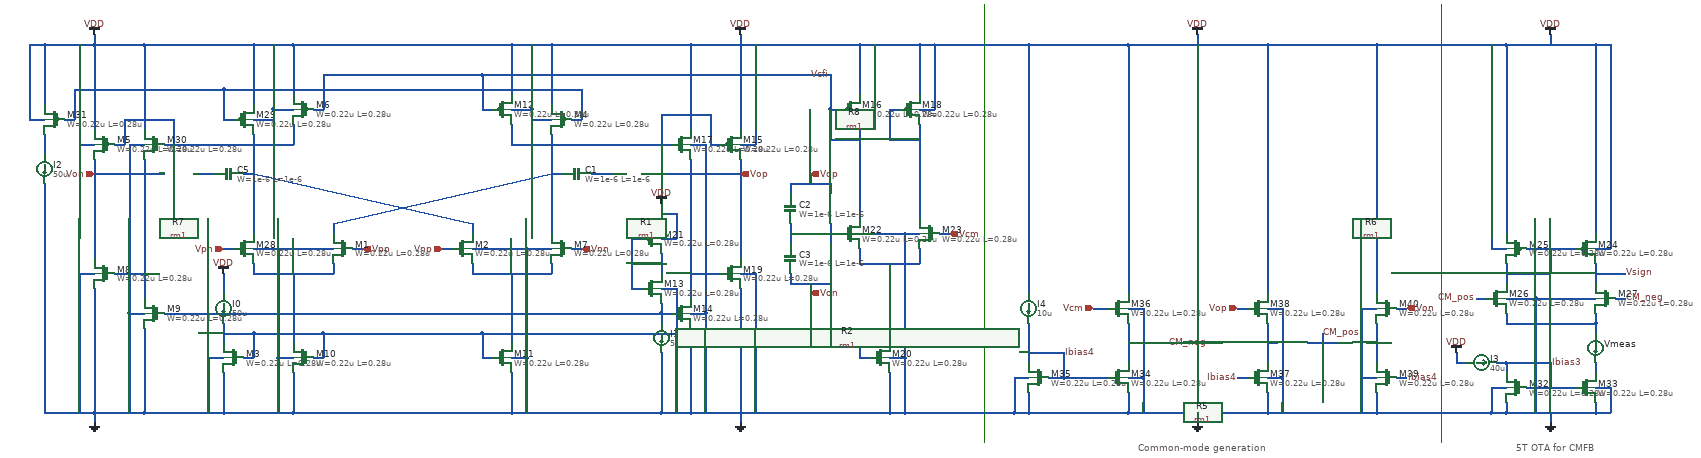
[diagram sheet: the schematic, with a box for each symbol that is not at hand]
v {xschem version=3.4.8RC file_version=1.3}
G {}
K {}
V {}
S {}
F {}
E {}
L 4 2030 -1660 2030 -780 {}
L 4 2950 -1660 2950 -780 {}
T {5T OTA for CMFB} 3100 -780 0 0 0.4 0.4 {}
T {Common-mode generation} 2340 -780 0 0 0.4 0.4 {}
N 560 -1400 560 -1200 {lab=#net1}
N 720 -1140 720 -1120 {lab=#net2}
N 560 -1120 720 -1120 {lab=#net2}
N 560 -1140 560 -1120 {lab=#net2}
N 1160 -1400 1160 -1200 {lab=#net3}
N 1000 -1140 1000 -1120 {lab=#net4}
N 1000 -1120 1160 -1120 {lab=#net4}
N 1160 -1140 1160 -1120 {lab=#net4}
N 140 -1400 140 -1360 {lab=#net5}
N 140 -1580 140 -1460 {lab=VDD}
N 140 -1580 240 -1580 {lab=VDD}
N 240 -1580 340 -1580 {lab=VDD}
N 140 -1300 140 -840 {lab=GND}
N 240 -1090 240 -840 {lab=GND}
N 140 -840 240 -840 {lab=GND}
N 340 -1010 340 -840 {lab=GND}
N 240 -840 340 -840 {lab=GND}
N 500 -1430 520 -1430 {lab=#net6}
N 280 -1120 340 -1120 {lab=#net7}
N 340 -840 500 -840 {lab=GND}
N 500 -840 640 -840 {lab=GND}
N 640 -840 1080 -840 {lab=GND}
N 560 -1580 560 -1460 {lab=VDD}
N 340 -1580 560 -1580 {lab=VDD}
N 720 -1220 720 -1200 {lab=#net3}
N 1000 -1220 1000 -1200 {lab=#net1}
N 240 -1350 240 -1150 {lab=Von}
N 340 -1350 340 -1070 {lab=#net7}
N 240 -1580 240 -1410 {lab=VDD}
N 340 -1580 340 -1410 {lab=VDD}
N 380 -1380 560 -1380 {lab=#net1}
N 400 -1430 400 -1380 {lab=#net1}
N 300 -1430 400 -1430 {lab=#net1}
N 300 -1430 300 -1380 {lab=#net1}
N 280 -1380 300 -1380 {lab=#net1}
N 560 -1380 640 -1380 {lab=#net1}
N 640 -1420 640 -1380 {lab=#net1}
N 640 -1580 640 -1480 {lab=VDD}
N 560 -1580 640 -1580 {lab=VDD}
N 680 -1450 700 -1450 {lab=Vcfi}
N 1020 -1450 1040 -1450 {lab=Vcfi}
N 1080 -1420 1080 -1380 {lab=#net3}
N 1080 -1380 1160 -1380 {lab=#net3}
N 640 -1580 1080 -1580 {lab=VDD}
N 1080 -1580 1080 -1480 {lab=VDD}
N 1080 -1580 1160 -1580 {lab=VDD}
N 1160 -1580 1160 -1460 {lab=VDD}
N 1480 -1380 1500 -1380 {lab=#net3}
N 1480 -1440 1480 -1380 {lab=#net3}
N 1380 -1440 1480 -1440 {lab=#net3}
N 1380 -1440 1380 -1380 {lab=#net3}
N 1440 -1580 1440 -1410 {lab=VDD}
N 1540 -1580 1540 -1410 {lab=VDD}
N 1440 -1580 1540 -1580 {lab=VDD}
N 1440 -1350 1440 -1070 {lab=#net8}
N 1440 -1010 1440 -840 {lab=GND}
N 1440 -1120 1500 -1120 {lab=#net8}
N 1540 -1350 1540 -1150 {lab=Vop}
N 1540 -1090 1540 -840 {lab=GND}
N 1440 -840 1540 -840 {lab=GND}
N 1320 -1090 1340 -1090 {lab=#net9}
N 1320 -1190 1320 -1090 {lab=#net9}
N 1320 -1190 1340 -1190 {lab=#net9}
N 1380 -1160 1380 -1120 {lab=#net9}
N 1320 -1140 1380 -1140 {lab=#net9}
N 1380 -1040 1380 -1020 {lab=#net10}
N 1380 -1060 1380 -1040 {lab=#net10}
N 1380 -960 1380 -840 {lab=GND}
N 1080 -840 1380 -840 {lab=GND}
N 1380 -840 1440 -840 {lab=GND}
N 380 -1040 1380 -1040 {lab=#net10}
N 1380 -1040 1400 -1040 {lab=#net10}
N 1160 -1380 1400 -1380 {lab=#net3}
N 1160 -1580 1440 -1580 {lab=VDD}
N 1200 -1170 1220 -1170 {lab=Vnn}
N 940 -1170 960 -1170 {lab=Vnp}
N 760 -1170 780 -1170 {lab=Vpp}
N 500 -1170 520 -1170 {lab=Vpn}
N 1720 -1450 1740 -1450 {lab=Vcfi}
N 1720 -1450 1720 -1390 {lab=Vcfi}
N 1720 -1390 1780 -1390 {lab=Vcfi}
N 1840 -1450 1860 -1450 {lab=#net11}
N 1840 -1450 1840 -1390 {lab=#net11}
N 1840 -1390 1900 -1390 {lab=#net11}
N 720 -1220 1160 -1320 {lab=#net3}
N 560 -1320 1000 -1220 {lab=#net1}
N 1780 -1420 1780 -1230 {lab=Vcfi}
N 1900 -1420 1900 -1230 {lab=#net11}
N 1720 -1220 1720 -1180 {lab=#net12}
N 1640 -1220 1640 -1180 {lab=#net12}
N 1640 -1300 1640 -1280 {lab=Vop}
N 1640 -1300 1720 -1300 {lab=Vop}
N 1720 -1300 1720 -1280 {lab=Vop}
N 1720 -1120 1720 -1100 {lab=Von}
N 1640 -1100 1720 -1100 {lab=Von}
N 1640 -1120 1640 -1100 {lab=Von}
N 1720 -1200 1740 -1200 {lab=#net12}
N 1640 -1200 1720 -1200 {lab=#net12}
N 1540 -1580 1780 -1580 {lab=VDD}
N 1780 -1580 1780 -1480 {lab=VDD}
N 1780 -1580 1900 -1580 {lab=VDD}
N 1900 -1580 1900 -1480 {lab=VDD}
N 1900 -1170 1900 -1140 {lab=#net13}
N 1780 -1140 1900 -1140 {lab=#net13}
N 1780 -1170 1780 -1140 {lab=#net13}
N 1540 -840 1840 -840 {lab=GND}
N 1940 -1200 1960 -1200 {lab=Vcm}
N 1680 -1320 1680 -1300 {lab=Vop}
N 1680 -1100 1680 -1080 {lab=Von}
N 500 -920 500 -840 {lab=GND}
N 1080 -920 1080 -840 {lab=GND}
N 1840 -920 1840 -840 {lab=GND}
N 1840 -1140 1840 -980 {lab=#net13}
N 640 -1120 640 -980 {lab=#net2}
N 1080 -1120 1080 -980 {lab=#net4}
N 500 -1000 560 -1000 {lab=#net14}
N 560 -1000 560 -950 {lab=#net14}
N 540 -950 560 -950 {lab=#net14}
N 680 -950 700 -950 {lab=#net14}
N 700 -1000 700 -950 {lab=#net14}
N 560 -1000 700 -1000 {lab=#net14}
N 700 -1000 1020 -1000 {lab=#net14}
N 1020 -1000 1020 -950 {lab=#net14}
N 1020 -950 1040 -950 {lab=#net14}
N 1020 -1000 1780 -1000 {lab=#net14}
N 1780 -1000 1780 -950 {lab=#net14}
N 1780 -950 1800 -950 {lab=#net14}
N 180 -1430 200 -1430 {lab=#net6}
N 640 -920 640 -840 {lab=GND}
N 1200 -1430 1220 -1430 {lab=#net6}
N 600 -1450 640 -1450 {lab=VDD}
N 600 -1450 600 -1430 {lab=VDD}
N 560 -1430 600 -1430 {lab=VDD}
N 1080 -1450 1120 -1450 {lab=VDD}
N 1120 -1450 1120 -1430 {lab=VDD}
N 1120 -1430 1160 -1430 {lab=VDD}
N 1900 -1450 1930 -1450 {lab=VDD}
N 1780 -1450 1810 -1450 {lab=VDD}
N 1540 -1380 1570 -1380 {lab=VDD}
N 1840 -950 1870 -950 {lab=GND}
N 1440 -1040 1470 -1040 {lab=GND}
N 1380 -1090 1410 -1090 {lab=GND}
N 1540 -1120 1570 -1120 {lab=GND}
N 1440 -1380 1470 -1380 {lab=GND}
N 470 -950 500 -950 {lab=GND}
N 610 -950 640 -950 {lab=GND}
N 310 -1040 340 -1040 {lab=GND}
N 210 -1120 240 -1120 {lab=GND}
N 310 -1380 340 -1380 {lab=GND}
N 3120 -1170 3220 -1170 {lab=#net15}
N 3300 -1070 3320 -1070 {lab=CM_neg}
N 3020 -1070 3040 -1070 {lab=CM_pos}
N 3170 -1170 3170 -1120 {lab=#net15}
N 3080 -1120 3170 -1120 {lab=#net15}
N 3080 -1040 3080 -1020 {lab=#net16}
N 3080 -1020 3260 -1020 {lab=#net16}
N 3260 -1040 3260 -1020 {lab=#net16}
N 3120 -890 3220 -890 {lab=Ibias3}
N 3170 -940 3170 -890 {lab=Ibias3}
N 3080 -940 3170 -940 {lab=Ibias3}
N 3260 -860 3260 -840 {lab=GND}
N 3080 -840 3260 -840 {lab=GND}
N 3080 -860 3080 -840 {lab=GND}
N 2860 -1050 2880 -1050 {lab=Von}
N 2540 -1050 2560 -1050 {lab=Vop}
N 3260 -1120 3320 -1120 {lab=Vsign}
N 2820 -1020 2820 -940 {lab=#net17}
N 2600 -1020 2600 -940 {lab=#net18}
N 2600 -880 2600 -840 {lab=GND}
N 2600 -840 2820 -840 {lab=GND}
N 2820 -880 2820 -840 {lab=GND}
N 2790 -910 2820 -910 {lab=GND}
N 2790 -910 2790 -840 {lab=GND}
N 2630 -910 2630 -840 {lab=GND}
N 2600 -910 2630 -910 {lab=GND}
N 2160 -910 2190 -910 {lab=Ibias4}
N 2190 -960 2190 -910 {lab=Ibias4}
N 2120 -960 2190 -960 {lab=Ibias4}
N 2190 -910 2280 -910 {lab=Ibias4}
N 2320 -1020 2320 -940 {lab=CM_neg}
N 2320 -840 2600 -840 {lab=GND}
N 2320 -880 2320 -840 {lab=GND}
N 2120 -840 2320 -840 {lab=GND}
N 2120 -880 2120 -840 {lab=GND}
N 2090 -910 2120 -910 {lab=GND}
N 2090 -910 2090 -840 {lab=GND}
N 2090 -840 2120 -840 {lab=GND}
N 2320 -910 2350 -910 {lab=GND}
N 2350 -910 2350 -840 {lab=GND}
N 2320 -1050 2350 -1050 {lab=GND}
N 2350 -1050 2350 -910 {lab=GND}
N 2600 -1050 2630 -1050 {lab=GND}
N 2630 -1050 2630 -910 {lab=GND}
N 2790 -1050 2820 -1050 {lab=GND}
N 2790 -1050 2790 -910 {lab=GND}
N 2250 -1050 2280 -1050 {lab=Vcm}
N 2320 -980 2400 -980 {lab=CM_neg}
N 2680 -980 2740 -980 {lab=CM_pos}
N 2600 -980 2620 -980 {lab=#net18}
N 2800 -980 2820 -980 {lab=#net17}
N 2710 -1000 2710 -980 {lab=CM_pos}
N 2540 -910 2560 -910 {lab=Ibias4}
N 2860 -910 2880 -910 {lab=Ibias4}
N 1720 -1520 1720 -1450 {lab=Vcfi}
N 1020 -1520 1720 -1520 {lab=Vcfi}
N 1020 -1520 1020 -1450 {lab=Vcfi}
N 700 -1520 1020 -1520 {lab=Vcfi}
N 700 -1520 700 -1450 {lab=Vcfi}
N 1220 -1490 1220 -1430 {lab=#net6}
N 500 -1490 1220 -1490 {lab=#net6}
N 500 -1490 500 -1430 {lab=#net6}
N 200 -1490 500 -1490 {lab=#net6}
N 200 -1490 200 -1430 {lab=#net6}
N 600 -1580 600 -1450 {lab=VDD}
N 1120 -1580 1120 -1450 {lab=VDD}
N 3080 -1140 3080 -1100 {lab=#net15}
N 3260 -1140 3260 -1100 {lab=Vsign}
N 3060 -940 3080 -940 {lab=Ibias3}
N 2980 -940 3000 -940 {lab=VDD}
N 2980 -960 2980 -940 {lab=VDD}
N 3080 -940 3080 -920 {lab=Ibias3}
N 3260 -940 3260 -920 {lab=#net19}
N 3260 -1020 3260 -1000 {lab=#net16}
N 3050 -1170 3080 -1170 {lab=VDD}
N 3260 -1170 3290 -1170 {lab=VDD}
N 3260 -890 3290 -890 {lab=GND}
N 3290 -890 3290 -840 {lab=GND}
N 3260 -840 3290 -840 {lab=GND}
N 3050 -840 3080 -840 {lab=GND}
N 3050 -890 3050 -840 {lab=GND}
N 3050 -890 3080 -890 {lab=GND}
N 1870 -950 1870 -840 {lab=GND}
N 1840 -840 1870 -840 {lab=GND}
N 1470 -1040 1470 -840 {lab=GND}
N 1080 -950 1110 -950 {lab=GND}
N 1110 -950 1110 -840 {lab=GND}
N 610 -950 610 -840 {lab=GND}
N 470 -950 470 -840 {lab=GND}
N 310 -1040 310 -840 {lab=GND}
N 210 -1120 210 -840 {lab=GND}
N 540 -1320 560 -1320 {lab=#net1}
N 440 -1320 480 -1320 {lab=#net20}
N 240 -1320 380 -1320 {lab=Von}
N 1160 -1320 1180 -1320 {lab=#net3}
N 1240 -1320 1280 -1320 {lab=#net21}
N 1340 -1320 1540 -1320 {lab=Vop}
N 1930 -1580 1930 -1450 {lab=VDD}
N 1900 -1580 1930 -1580 {lab=VDD}
N 1810 -1580 1810 -1450 {lab=VDD}
N 1570 -1580 1570 -1380 {lab=VDD}
N 210 -1380 240 -1380 {lab=VDD}
N 210 -1580 210 -1380 {lab=VDD}
N 110 -1430 140 -1430 {lab=VDD}
N 110 -1580 110 -1430 {lab=VDD}
N 110 -1580 140 -1580 {lab=VDD}
N 1870 -1200 1870 -950 {lab=GND}
N 1870 -1200 1900 -1200 {lab=GND}
N 1780 -1200 1870 -1200 {lab=GND}
N 1470 -1380 1470 -1040 {lab=GND}
N 1570 -1120 1570 -840 {lab=GND}
N 1110 -1170 1110 -950 {lab=GND}
N 1110 -1170 1160 -1170 {lab=GND}
N 1000 -1170 1110 -1170 {lab=GND}
N 610 -1170 610 -950 {lab=GND}
N 560 -1170 610 -1170 {lab=GND}
N 610 -1170 720 -1170 {lab=GND}
N 3140 -1070 3140 -840 {lab=GND}
N 3080 -1070 3140 -1070 {lab=GND}
N 3140 -1070 3260 -1070 {lab=GND}
N 500 -1120 500 -1080 {lab=VDD}
N 500 -1020 500 -980 {lab=#net14}
N 1380 -1260 1380 -1220 {lab=VDD}
N 1380 -1190 1410 -1190 {lab=VDD}
N 1410 -1240 1410 -1190 {lab=VDD}
N 1380 -1240 1410 -1240 {lab=VDD}
N 1410 -1090 1410 -840 {lab=GND}
N 2120 -1020 2120 -940 {lab=Ibias4}
N 240 -840 240 -820 {lab=GND}
N 1540 -840 1540 -820 {lab=GND}
N 2460 -840 2460 -820 {lab=GND}
N 3170 -840 3170 -820 {lab=GND}
N 240 -1600 240 -1580 {lab=VDD}
N 1540 -1600 1540 -1580 {lab=VDD}
N 2820 -840 3050 -840 {lab=GND}
N 2120 -1580 2120 -1080 {lab=VDD}
N 2320 -1580 2320 -1080 {lab=VDD}
N 2120 -1580 2320 -1580 {lab=VDD}
N 2600 -1580 2600 -1080 {lab=VDD}
N 2320 -1580 2600 -1580 {lab=VDD}
N 2820 -1580 2820 -1080 {lab=VDD}
N 2600 -1580 2820 -1580 {lab=VDD}
N 3080 -1580 3080 -1200 {lab=VDD}
N 2820 -1580 3080 -1580 {lab=VDD}
N 3260 -1580 3260 -1200 {lab=VDD}
N 3080 -1580 3260 -1580 {lab=VDD}
N 3050 -1580 3050 -1170 {lab=VDD}
N 3290 -1580 3290 -1170 {lab=VDD}
N 3260 -1580 3290 -1580 {lab=VDD}
N 2460 -1600 2460 -1580 {lab=VDD}
N 3170 -1600 3170 -1580 {lab=VDD}
N 1930 -1580 2120 -1580 {lab=VDD}
N 1870 -840 2090 -840 {lab=GND}
N 310 -1380 310 -1040 {lab=GND}
C {ipin.sym} 500 -1170 0 0 {name=p1 lab=Vpn}
C {ipin.sym} 780 -1170 0 1 {name=p2 lab=Vpp}
C {ipin.sym} 940 -1170 0 0 {name=p3 lab=Vnp}
C {ipin.sym} 1220 -1170 0 1 {name=p4 lab=Vnn}
C {isource.sym} 500 -1050 0 0 {name=I0 value=50u}
C {isource.sym} 1380 -990 0 0 {name=I1 value=50u}
C {isource.sym} 140 -1330 0 0 {name=I2 value=50u}
C {opin.sym} 1680 -1080 0 0 {name=p12 lab=Von}
C {opin.sym} 1680 -1320 0 0 {name=p10 lab=Vop}
C {opin.sym} 1540 -1320 0 0 {name=p11 lab=Vop}
C {opin.sym} 240 -1320 0 1 {name=p13 lab=Von}
C {lab_wire.sym} 1720 -1520 0 0 {name=p14 sig_type=std_logic lab=Vcfi}
C {symbols/nfet_03v3.sym} 540 -1170 0 0 {name=M28
L=0.28u
W=0.22u
nf=1
m=1
ad="'int((nf+1)/2) * W/nf * 0.18u'"
pd="'2*int((nf+1)/2) * (W/nf + 0.18u)'"
as="'int((nf+2)/2) * W/nf * 0.18u'"
ps="'2*int((nf+2)/2) * (W/nf + 0.18u)'"
nrd="'0.18u / W'" nrs="'0.18u / W'"
sa=0 sb=0 sd=0
model=nfet_03v3
spiceprefix=X
}
C {symbols/pfet_03v3.sym} 540 -1430 0 0 {name=M29
L=0.28u
W=0.22u
nf=1
m=1
ad="'int((nf+1)/2) * W/nf * 0.18u'"
pd="'2*int((nf+1)/2) * (W/nf + 0.18u)'"
as="'int((nf+2)/2) * W/nf * 0.18u'"
ps="'2*int((nf+2)/2) * (W/nf + 0.18u)'"
nrd="'0.18u / W'" nrs="'0.18u / W'"
sa=0 sb=0 sd=0
model=pfet_03v3
spiceprefix=X
}
C {gnd.sym} 240 -820 0 0 {name=l1 lab=GND}
C {vdd.sym} 240 -1600 0 0 {name=l2 lab=VDD}
C {symbols/nfet_03v3.sym} 360 -1380 0 1 {name=M30
L=0.28u
W=0.22u
nf=1
m=1
ad="'int((nf+1)/2) * W/nf * 0.18u'"
pd="'2*int((nf+1)/2) * (W/nf + 0.18u)'"
as="'int((nf+2)/2) * W/nf * 0.18u'"
ps="'2*int((nf+2)/2) * (W/nf + 0.18u)'"
nrd="'0.18u / W'" nrs="'0.18u / W'"
sa=0 sb=0 sd=0
model=nfet_03v3
spiceprefix=X
}
C {symbols/pfet_03v3.sym} 160 -1430 0 1 {name=M31
L=0.28u
W=0.22u
nf=1
m=1
ad="'int((nf+1)/2) * W/nf * 0.18u'"
pd="'2*int((nf+1)/2) * (W/nf + 0.18u)'"
as="'int((nf+2)/2) * W/nf * 0.18u'"
ps="'2*int((nf+2)/2) * (W/nf + 0.18u)'"
nrd="'0.18u / W'" nrs="'0.18u / W'"
sa=0 sb=0 sd=0
model=pfet_03v3
spiceprefix=X
}
C {symbols/pfet_03v3.sym} 260 -1380 0 1 {name=M5
L=0.28u
W=0.22u
nf=1
m=1
ad="'int((nf+1)/2) * W/nf * 0.18u'"
pd="'2*int((nf+1)/2) * (W/nf + 0.18u)'"
as="'int((nf+2)/2) * W/nf * 0.18u'"
ps="'2*int((nf+2)/2) * (W/nf + 0.18u)'"
nrd="'0.18u / W'" nrs="'0.18u / W'"
sa=0 sb=0 sd=0
model=pfet_03v3
spiceprefix=X
}
C {symbols/pfet_03v3.sym} 660 -1450 0 1 {name=M6
L=0.28u
W=0.22u
nf=1
m=1
ad="'int((nf+1)/2) * W/nf * 0.18u'"
pd="'2*int((nf+1)/2) * (W/nf + 0.18u)'"
as="'int((nf+2)/2) * W/nf * 0.18u'"
ps="'2*int((nf+2)/2) * (W/nf + 0.18u)'"
nrd="'0.18u / W'" nrs="'0.18u / W'"
sa=0 sb=0 sd=0
model=pfet_03v3
spiceprefix=X
}
C {symbols/pfet_03v3.sym} 1180 -1430 0 1 {name=M4
L=0.28u
W=0.22u
nf=1
m=1
ad="'int((nf+1)/2) * W/nf * 0.18u'"
pd="'2*int((nf+1)/2) * (W/nf + 0.18u)'"
as="'int((nf+2)/2) * W/nf * 0.18u'"
ps="'2*int((nf+2)/2) * (W/nf + 0.18u)'"
nrd="'0.18u / W'" nrs="'0.18u / W'"
sa=0 sb=0 sd=0
model=pfet_03v3
spiceprefix=X
}
C {symbols/pfet_03v3.sym} 1060 -1450 0 0 {name=M12
L=0.28u
W=0.22u
nf=1
m=1
ad="'int((nf+1)/2) * W/nf * 0.18u'"
pd="'2*int((nf+1)/2) * (W/nf + 0.18u)'"
as="'int((nf+2)/2) * W/nf * 0.18u'"
ps="'2*int((nf+2)/2) * (W/nf + 0.18u)'"
nrd="'0.18u / W'" nrs="'0.18u / W'"
sa=0 sb=0 sd=0
model=pfet_03v3
spiceprefix=X
}
C {symbols/pfet_03v3.sym} 1520 -1380 0 0 {name=M15
L=0.28u
W=0.22u
nf=1
m=1
ad="'int((nf+1)/2) * W/nf * 0.18u'"
pd="'2*int((nf+1)/2) * (W/nf + 0.18u)'"
as="'int((nf+2)/2) * W/nf * 0.18u'"
ps="'2*int((nf+2)/2) * (W/nf + 0.18u)'"
nrd="'0.18u / W'" nrs="'0.18u / W'"
sa=0 sb=0 sd=0
model=pfet_03v3
spiceprefix=X
}
C {symbols/pfet_03v3.sym} 1760 -1450 0 0 {name=M16
L=0.28u
W=0.22u
nf=1
m=1
ad="'int((nf+1)/2) * W/nf * 0.18u'"
pd="'2*int((nf+1)/2) * (W/nf + 0.18u)'"
as="'int((nf+2)/2) * W/nf * 0.18u'"
ps="'2*int((nf+2)/2) * (W/nf + 0.18u)'"
nrd="'0.18u / W'" nrs="'0.18u / W'"
sa=0 sb=0 sd=0
model=pfet_03v3
spiceprefix=X
}
C {symbols/pfet_03v3.sym} 1880 -1450 0 0 {name=M18
L=0.28u
W=0.22u
nf=1
m=1
ad="'int((nf+1)/2) * W/nf * 0.18u'"
pd="'2*int((nf+1)/2) * (W/nf + 0.18u)'"
as="'int((nf+2)/2) * W/nf * 0.18u'"
ps="'2*int((nf+2)/2) * (W/nf + 0.18u)'"
nrd="'0.18u / W'" nrs="'0.18u / W'"
sa=0 sb=0 sd=0
model=pfet_03v3
spiceprefix=X
}
C {symbols/pfet_03v3.sym} 1360 -1190 0 0 {name=M21
L=0.28u
W=0.22u
nf=1
m=1
ad="'int((nf+1)/2) * W/nf * 0.18u'"
pd="'2*int((nf+1)/2) * (W/nf + 0.18u)'"
as="'int((nf+2)/2) * W/nf * 0.18u'"
ps="'2*int((nf+2)/2) * (W/nf + 0.18u)'"
nrd="'0.18u / W'" nrs="'0.18u / W'"
sa=0 sb=0 sd=0
model=pfet_03v3
spiceprefix=X
}
C {symbols/nfet_03v3.sym} 740 -1170 0 1 {name=M1
L=0.28u
W=0.22u
nf=1
m=1
ad="'int((nf+1)/2) * W/nf * 0.18u'"
pd="'2*int((nf+1)/2) * (W/nf + 0.18u)'"
as="'int((nf+2)/2) * W/nf * 0.18u'"
ps="'2*int((nf+2)/2) * (W/nf + 0.18u)'"
nrd="'0.18u / W'" nrs="'0.18u / W'"
sa=0 sb=0 sd=0
model=nfet_03v3
spiceprefix=X
}
C {symbols/nfet_03v3.sym} 980 -1170 0 0 {name=M2
L=0.28u
W=0.22u
nf=1
m=1
ad="'int((nf+1)/2) * W/nf * 0.18u'"
pd="'2*int((nf+1)/2) * (W/nf + 0.18u)'"
as="'int((nf+2)/2) * W/nf * 0.18u'"
ps="'2*int((nf+2)/2) * (W/nf + 0.18u)'"
nrd="'0.18u / W'" nrs="'0.18u / W'"
sa=0 sb=0 sd=0
model=nfet_03v3
spiceprefix=X
}
C {symbols/nfet_03v3.sym} 1180 -1170 0 1 {name=M7
L=0.28u
W=0.22u
nf=1
m=1
ad="'int((nf+1)/2) * W/nf * 0.18u'"
pd="'2*int((nf+1)/2) * (W/nf + 0.18u)'"
as="'int((nf+2)/2) * W/nf * 0.18u'"
ps="'2*int((nf+2)/2) * (W/nf + 0.18u)'"
nrd="'0.18u / W'" nrs="'0.18u / W'"
sa=0 sb=0 sd=0
model=nfet_03v3
spiceprefix=X
}
C {symbols/nfet_03v3.sym} 520 -950 0 1 {name=M3
L=0.28u
W=0.22u
nf=1
m=1
ad="'int((nf+1)/2) * W/nf * 0.18u'"
pd="'2*int((nf+1)/2) * (W/nf + 0.18u)'"
as="'int((nf+2)/2) * W/nf * 0.18u'"
ps="'2*int((nf+2)/2) * (W/nf + 0.18u)'"
nrd="'0.18u / W'" nrs="'0.18u / W'"
sa=0 sb=0 sd=0
model=nfet_03v3
spiceprefix=X
}
C {symbols/nfet_03v3.sym} 660 -950 0 1 {name=M10
L=0.28u
W=0.22u
nf=1
m=1
ad="'int((nf+1)/2) * W/nf * 0.18u'"
pd="'2*int((nf+1)/2) * (W/nf + 0.18u)'"
as="'int((nf+2)/2) * W/nf * 0.18u'"
ps="'2*int((nf+2)/2) * (W/nf + 0.18u)'"
nrd="'0.18u / W'" nrs="'0.18u / W'"
sa=0 sb=0 sd=0
model=nfet_03v3
spiceprefix=X
}
C {symbols/nfet_03v3.sym} 1060 -950 0 0 {name=M11
L=0.28u
W=0.22u
nf=1
m=1
ad="'int((nf+1)/2) * W/nf * 0.18u'"
pd="'2*int((nf+1)/2) * (W/nf + 0.18u)'"
as="'int((nf+2)/2) * W/nf * 0.18u'"
ps="'2*int((nf+2)/2) * (W/nf + 0.18u)'"
nrd="'0.18u / W'" nrs="'0.18u / W'"
sa=0 sb=0 sd=0
model=nfet_03v3
spiceprefix=X
}
C {symbols/nfet_03v3.sym} 1360 -1090 0 0 {name=M13
L=0.28u
W=0.22u
nf=1
m=1
ad="'int((nf+1)/2) * W/nf * 0.18u'"
pd="'2*int((nf+1)/2) * (W/nf + 0.18u)'"
as="'int((nf+2)/2) * W/nf * 0.18u'"
ps="'2*int((nf+2)/2) * (W/nf + 0.18u)'"
nrd="'0.18u / W'" nrs="'0.18u / W'"
sa=0 sb=0 sd=0
model=nfet_03v3
spiceprefix=X
}
C {symbols/nfet_03v3.sym} 1420 -1040 0 0 {name=M14
L=0.28u
W=0.22u
nf=1
m=1
ad="'int((nf+1)/2) * W/nf * 0.18u'"
pd="'2*int((nf+1)/2) * (W/nf + 0.18u)'"
as="'int((nf+2)/2) * W/nf * 0.18u'"
ps="'2*int((nf+2)/2) * (W/nf + 0.18u)'"
nrd="'0.18u / W'" nrs="'0.18u / W'"
sa=0 sb=0 sd=0
model=nfet_03v3
spiceprefix=X
}
C {symbols/nfet_03v3.sym} 1520 -1120 0 0 {name=M19
L=0.28u
W=0.22u
nf=1
m=1
ad="'int((nf+1)/2) * W/nf * 0.18u'"
pd="'2*int((nf+1)/2) * (W/nf + 0.18u)'"
as="'int((nf+2)/2) * W/nf * 0.18u'"
ps="'2*int((nf+2)/2) * (W/nf + 0.18u)'"
nrd="'0.18u / W'" nrs="'0.18u / W'"
sa=0 sb=0 sd=0
model=nfet_03v3
spiceprefix=X
}
C {symbols/nfet_03v3.sym} 1820 -950 0 0 {name=M20
L=0.28u
W=0.22u
nf=1
m=1
ad="'int((nf+1)/2) * W/nf * 0.18u'"
pd="'2*int((nf+1)/2) * (W/nf + 0.18u)'"
as="'int((nf+2)/2) * W/nf * 0.18u'"
ps="'2*int((nf+2)/2) * (W/nf + 0.18u)'"
nrd="'0.18u / W'" nrs="'0.18u / W'"
sa=0 sb=0 sd=0
model=nfet_03v3
spiceprefix=X
}
C {symbols/nfet_03v3.sym} 1760 -1200 0 0 {name=M22
L=0.28u
W=0.22u
nf=1
m=1
ad="'int((nf+1)/2) * W/nf * 0.18u'"
pd="'2*int((nf+1)/2) * (W/nf + 0.18u)'"
as="'int((nf+2)/2) * W/nf * 0.18u'"
ps="'2*int((nf+2)/2) * (W/nf + 0.18u)'"
nrd="'0.18u / W'" nrs="'0.18u / W'"
sa=0 sb=0 sd=0
model=nfet_03v3
spiceprefix=X
}
C {symbols/nfet_03v3.sym} 1420 -1380 0 0 {name=M17
L=0.28u
W=0.22u
nf=1
m=1
ad="'int((nf+1)/2) * W/nf * 0.18u'"
pd="'2*int((nf+1)/2) * (W/nf + 0.18u)'"
as="'int((nf+2)/2) * W/nf * 0.18u'"
ps="'2*int((nf+2)/2) * (W/nf + 0.18u)'"
nrd="'0.18u / W'" nrs="'0.18u / W'"
sa=0 sb=0 sd=0
model=nfet_03v3
spiceprefix=X
}
C {symbols/nfet_03v3.sym} 260 -1120 0 1 {name=M8
L=0.28u
W=0.22u
nf=1
m=1
ad="'int((nf+1)/2) * W/nf * 0.18u'"
pd="'2*int((nf+1)/2) * (W/nf + 0.18u)'"
as="'int((nf+2)/2) * W/nf * 0.18u'"
ps="'2*int((nf+2)/2) * (W/nf + 0.18u)'"
nrd="'0.18u / W'" nrs="'0.18u / W'"
sa=0 sb=0 sd=0
model=nfet_03v3
spiceprefix=X
}
C {symbols/nfet_03v3.sym} 360 -1040 0 1 {name=M9
L=0.28u
W=0.22u
nf=1
m=1
ad="'int((nf+1)/2) * W/nf * 0.18u'"
pd="'2*int((nf+1)/2) * (W/nf + 0.18u)'"
as="'int((nf+2)/2) * W/nf * 0.18u'"
ps="'2*int((nf+2)/2) * (W/nf + 0.18u)'"
nrd="'0.18u / W'" nrs="'0.18u / W'"
sa=0 sb=0 sd=0
model=nfet_03v3
spiceprefix=X
}
C {symbols/nfet_03v3.sym} 1920 -1200 0 1 {name=M23
L=0.28u
W=0.22u
nf=1
m=1
ad="'int((nf+1)/2) * W/nf * 0.18u'"
pd="'2*int((nf+1)/2) * (W/nf + 0.18u)'"
as="'int((nf+2)/2) * W/nf * 0.18u'"
ps="'2*int((nf+2)/2) * (W/nf + 0.18u)'"
nrd="'0.18u / W'" nrs="'0.18u / W'"
sa=0 sb=0 sd=0
model=nfet_03v3
spiceprefix=X
}
C {gnd.sym} 1540 -820 0 0 {name=l11 lab=GND}
C {vdd.sym} 1540 -1600 0 0 {name=l12 lab=VDD}
C {symbols/pfet_03v3.sym} 3240 -1170 0 0 {name=M24
L=0.28u
W=0.22u
nf=1
m=1
ad="'int((nf+1)/2) * W/nf * 0.18u'"
pd="'2*int((nf+1)/2) * (W/nf + 0.18u)'"
as="'int((nf+2)/2) * W/nf * 0.18u'"
ps="'2*int((nf+2)/2) * (W/nf + 0.18u)'"
nrd="'0.18u / W'" nrs="'0.18u / W'"
sa=0 sb=0 sd=0
model=pfet_03v3
spiceprefix=X
}
C {symbols/pfet_03v3.sym} 3100 -1170 0 1 {name=M25
L=0.28u
W=0.22u
nf=1
m=1
ad="'int((nf+1)/2) * W/nf * 0.18u'"
pd="'2*int((nf+1)/2) * (W/nf + 0.18u)'"
as="'int((nf+2)/2) * W/nf * 0.18u'"
ps="'2*int((nf+2)/2) * (W/nf + 0.18u)'"
nrd="'0.18u / W'" nrs="'0.18u / W'"
sa=0 sb=0 sd=0
model=pfet_03v3
spiceprefix=X
}
C {symbols/nfet_03v3.sym} 3060 -1070 0 0 {name=M26
L=0.28u
W=0.22u
nf=1
m=1
ad="'int((nf+1)/2) * W/nf * 0.18u'"
pd="'2*int((nf+1)/2) * (W/nf + 0.18u)'"
as="'int((nf+2)/2) * W/nf * 0.18u'"
ps="'2*int((nf+2)/2) * (W/nf + 0.18u)'"
nrd="'0.18u / W'" nrs="'0.18u / W'"
sa=0 sb=0 sd=0
model=nfet_03v3
spiceprefix=X
}
C {symbols/nfet_03v3.sym} 3280 -1070 0 1 {name=M27
L=0.28u
W=0.22u
nf=1
m=1
ad="'int((nf+1)/2) * W/nf * 0.18u'"
pd="'2*int((nf+1)/2) * (W/nf + 0.18u)'"
as="'int((nf+2)/2) * W/nf * 0.18u'"
ps="'2*int((nf+2)/2) * (W/nf + 0.18u)'"
nrd="'0.18u / W'" nrs="'0.18u / W'"
sa=0 sb=0 sd=0
model=nfet_03v3
spiceprefix=X
}
C {vdd.sym} 3170 -1600 0 0 {name=l31 lab=VDD}
C {ammeter.sym} 3260 -970 0 0 {name=Vmeas savecurrent=true spice_ignore=0}
C {symbols/nfet_03v3.sym} 3100 -890 0 1 {name=M32
L=0.28u
W=0.22u
nf=1
m=1
ad="'int((nf+1)/2) * W/nf * 0.18u'"
pd="'2*int((nf+1)/2) * (W/nf + 0.18u)'"
as="'int((nf+2)/2) * W/nf * 0.18u'"
ps="'2*int((nf+2)/2) * (W/nf + 0.18u)'"
nrd="'0.18u / W'" nrs="'0.18u / W'"
sa=0 sb=0 sd=0
model=nfet_03v3
spiceprefix=X
}
C {symbols/nfet_03v3.sym} 3240 -890 0 0 {name=M33
L=0.28u
W=0.22u
nf=1
m=1
ad="'int((nf+1)/2) * W/nf * 0.18u'"
pd="'2*int((nf+1)/2) * (W/nf + 0.18u)'"
as="'int((nf+2)/2) * W/nf * 0.18u'"
ps="'2*int((nf+2)/2) * (W/nf + 0.18u)'"
nrd="'0.18u / W'" nrs="'0.18u / W'"
sa=0 sb=0 sd=0
model=nfet_03v3
spiceprefix=X
}
C {isource.sym} 3030 -940 3 0 {name=I3 value=40u}
C {vdd.sym} 2980 -960 0 0 {name=l32 lab=VDD}
C {gnd.sym} 3170 -820 0 0 {name=l33 lab=GND}
C {lab_wire.sym} 3320 -1120 0 1 {name=p15 sig_type=std_logic lab=Vsign}
C {lab_wire.sym} 3170 -940 0 1 {name=p16 sig_type=std_logic lab=Ibias3}
C {lab_wire.sym} 3320 -1070 0 1 {name=p5 sig_type=std_logic lab=CM_neg}
C {lab_wire.sym} 3020 -1070 0 0 {name=p6 sig_type=std_logic lab=CM_pos}
C {symbols/nfet_03v3.sym} 2300 -910 0 0 {name=M34
L=0.28u
W=0.22u
nf=1
m=1
ad="'int((nf+1)/2) * W/nf * 0.18u'"
pd="'2*int((nf+1)/2) * (W/nf + 0.18u)'"
as="'int((nf+2)/2) * W/nf * 0.18u'"
ps="'2*int((nf+2)/2) * (W/nf + 0.18u)'"
nrd="'0.18u / W'" nrs="'0.18u / W'"
sa=0 sb=0 sd=0
model=nfet_03v3
spiceprefix=X
}
C {symbols/nfet_03v3.sym} 2140 -910 0 1 {name=M35
L=0.28u
W=0.22u
nf=1
m=1
ad="'int((nf+1)/2) * W/nf * 0.18u'"
pd="'2*int((nf+1)/2) * (W/nf + 0.18u)'"
as="'int((nf+2)/2) * W/nf * 0.18u'"
ps="'2*int((nf+2)/2) * (W/nf + 0.18u)'"
nrd="'0.18u / W'" nrs="'0.18u / W'"
sa=0 sb=0 sd=0
model=nfet_03v3
spiceprefix=X
}
C {symbols/nfet_03v3.sym} 2300 -1050 0 0 {name=M36
L=0.28u
W=0.22u
nf=1
m=1
ad="'int((nf+1)/2) * W/nf * 0.18u'"
pd="'2*int((nf+1)/2) * (W/nf + 0.18u)'"
as="'int((nf+2)/2) * W/nf * 0.18u'"
ps="'2*int((nf+2)/2) * (W/nf + 0.18u)'"
nrd="'0.18u / W'" nrs="'0.18u / W'"
sa=0 sb=0 sd=0
model=nfet_03v3
spiceprefix=X
}
C {symbols/nfet_03v3.sym} 2580 -910 0 0 {name=M37
L=0.28u
W=0.22u
nf=1
m=1
ad="'int((nf+1)/2) * W/nf * 0.18u'"
pd="'2*int((nf+1)/2) * (W/nf + 0.18u)'"
as="'int((nf+2)/2) * W/nf * 0.18u'"
ps="'2*int((nf+2)/2) * (W/nf + 0.18u)'"
nrd="'0.18u / W'" nrs="'0.18u / W'"
sa=0 sb=0 sd=0
model=nfet_03v3
spiceprefix=X
}
C {symbols/nfet_03v3.sym} 2580 -1050 0 0 {name=M38
L=0.28u
W=0.22u
nf=1
m=1
ad="'int((nf+1)/2) * W/nf * 0.18u'"
pd="'2*int((nf+1)/2) * (W/nf + 0.18u)'"
as="'int((nf+2)/2) * W/nf * 0.18u'"
ps="'2*int((nf+2)/2) * (W/nf + 0.18u)'"
nrd="'0.18u / W'" nrs="'0.18u / W'"
sa=0 sb=0 sd=0
model=nfet_03v3
spiceprefix=X
}
C {symbols/nfet_03v3.sym} 2840 -910 0 1 {name=M39
L=0.28u
W=0.22u
nf=1
m=1
ad="'int((nf+1)/2) * W/nf * 0.18u'"
pd="'2*int((nf+1)/2) * (W/nf + 0.18u)'"
as="'int((nf+2)/2) * W/nf * 0.18u'"
ps="'2*int((nf+2)/2) * (W/nf + 0.18u)'"
nrd="'0.18u / W'" nrs="'0.18u / W'"
sa=0 sb=0 sd=0
model=nfet_03v3
spiceprefix=X
}
C {symbols/nfet_03v3.sym} 2840 -1050 0 1 {name=M40
L=0.28u
W=0.22u
nf=1
m=1
ad="'int((nf+1)/2) * W/nf * 0.18u'"
pd="'2*int((nf+1)/2) * (W/nf + 0.18u)'"
as="'int((nf+2)/2) * W/nf * 0.18u'"
ps="'2*int((nf+2)/2) * (W/nf + 0.18u)'"
nrd="'0.18u / W'" nrs="'0.18u / W'"
sa=0 sb=0 sd=0
model=nfet_03v3
spiceprefix=X
}
C {opin.sym} 2540 -1050 0 1 {name=p17 lab=Vop}
C {opin.sym} 2880 -1050 0 0 {name=p18 lab=Von}
C {gnd.sym} 2460 -820 0 0 {name=l34 lab=GND}
C {isource.sym} 2120 -1050 0 0 {name=I4 value=10u}
C {ipin.sym} 1960 -1200 0 1 {name=p20 lab=Vcm}
C {ipin.sym} 2250 -1050 0 0 {name=p21 lab=Vcm}
C {vdd.sym} 2460 -1600 0 0 {name=l35 lab=VDD}
C {lab_wire.sym} 2710 -1000 0 1 {name=p9 sig_type=std_logic lab=CM_pos}
C {lab_wire.sym} 2400 -980 0 1 {name=p19 sig_type=std_logic lab=CM_neg}
C {symbols/rm1.sym} 2650 -980 1 0 {name=R5
W=0.6e-6
L=0.6e-6
model=rm1
spiceprefix=X
m=1}
C {symbols/rm1.sym} 2770 -980 1 0 {name=R6
W=0.6e-6
L=0.6e-6
model=rm1
spiceprefix=X
m=1}
C {lab_wire.sym} 2190 -960 0 1 {name=p22 sig_type=std_logic lab=Ibias4}
C {lab_wire.sym} 2880 -910 0 1 {name=p23 sig_type=std_logic lab=Ibias4}
C {lab_wire.sym} 2540 -910 0 0 {name=p24 sig_type=std_logic lab=Ibias4}
C {symbols/rm1.sym} 410 -1320 3 0 {name=R7
W=0.6e-6
L=0.6e-6
model=rm1
spiceprefix=X
m=1}
C {symbols/cap_mim_2f0fF.sym} 510 -1320 3 0 {name=C5
W=1e-6
L=1e-6
model=cap_mim_2f0fF
spiceprefix=X
m=1}
C {symbols/rm1.sym} 1310 -1320 1 1 {name=R1
W=0.6e-6
L=0.6e-6
model=rm1
spiceprefix=X
m=1}
C {symbols/cap_mim_2f0fF.sym} 1210 -1320 1 1 {name=C1
W=1e-6
L=1e-6
model=cap_mim_2f0fF
spiceprefix=X
m=1}
C {vdd.sym} 500 -1120 0 0 {name=l3 lab=VDD}
C {vdd.sym} 1380 -1260 0 0 {name=l4 lab=VDD}
C {symbols/cap_mim_2f0fF.sym} 1640 -1250 0 1 {name=C2
W=1e-6
L=1e-6
model=cap_mim_2f0fF
spiceprefix=X
m=1}
C {symbols/rm1.sym} 1720 -1250 2 1 {name=R8
W=0.6e-6
L=0.6e-6
model=rm1
spiceprefix=X
m=1}
C {symbols/cap_mim_2f0fF.sym} 1640 -1150 0 1 {name=C3
W=1e-6
L=1e-6
model=cap_mim_2f0fF
spiceprefix=X
m=1}
C {symbols/rm1.sym} 1720 -1150 2 1 {name=R2
W=0.6e-6
L=0.6e-6
model=rm1
spiceprefix=X
m=1}
C {title-2.sym} 0 0 0 0 {name=l5 author="UFJF On Chip" rev=1.0 lock=true}
